##
## LEF for PtnCells ;
## created by Innovus v15.23-s045_1 on Fri Mar  6 05:47:07 2026
##

VERSION 5.8 ;

BUSBITCHARS "[]" ;
DIVIDERCHAR "/" ;

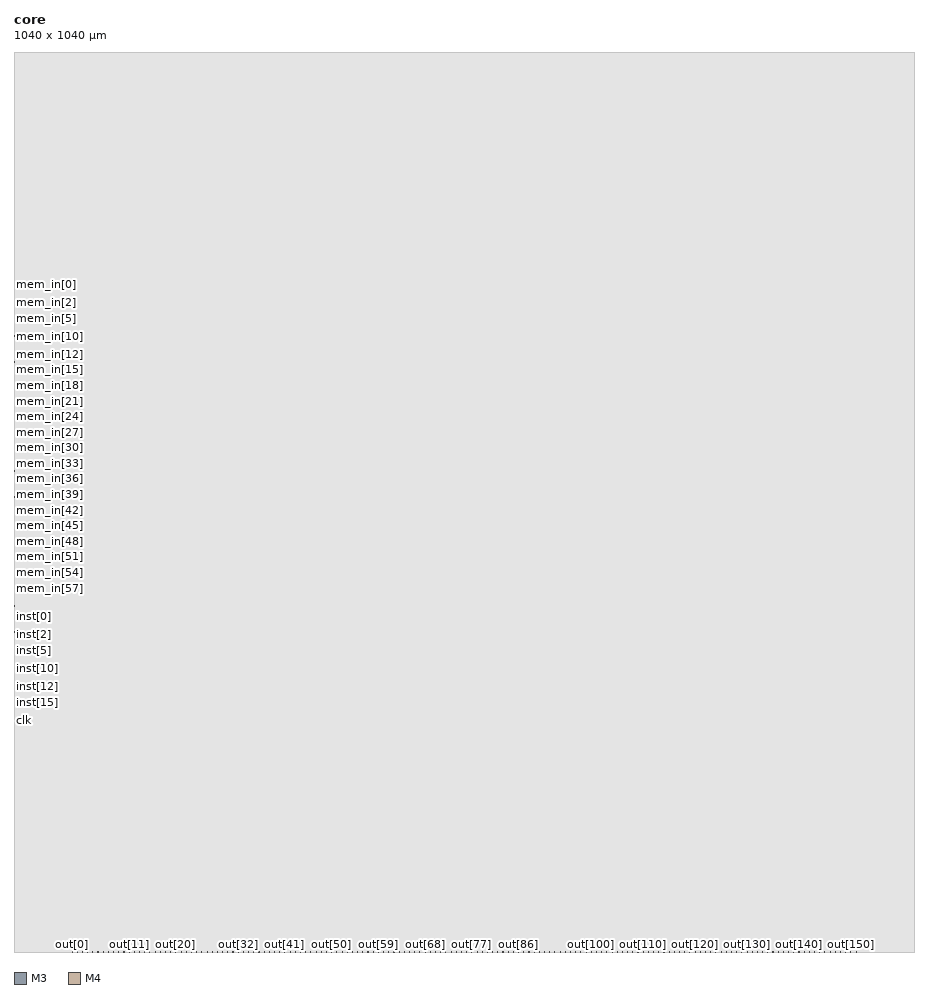
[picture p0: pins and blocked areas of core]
MACRO core
  CLASS BLOCK ;
  SIZE 1040.0000 BY 1040.0000 ;
  FOREIGN core 0.0000 0.0000 ;
  ORIGIN 0 0 ;
  SYMMETRY X Y R90 ;
  PIN clk
    DIRECTION INPUT ;
    USE SIGNAL ;
    PORT
      LAYER M3 ;
        RECT 0.0000 267.7500 0.5200 267.8500 ;
    END
  END clk
  PIN mem_in[63]
    DIRECTION INPUT ;
    USE SIGNAL ;
    PORT
      LAYER M3 ;
        RECT 0.0000 393.7500 0.5200 393.8500 ;
    END
  END mem_in[63]
  PIN mem_in[62]
    DIRECTION INPUT ;
    USE SIGNAL ;
    PORT
      LAYER M3 ;
        RECT 0.0000 399.7500 0.5200 399.8500 ;
    END
  END mem_in[62]
  PIN mem_in[61]
    DIRECTION INPUT ;
    USE SIGNAL ;
    PORT
      LAYER M3 ;
        RECT 0.0000 405.7500 0.5200 405.8500 ;
    END
  END mem_in[61]
  PIN mem_in[60]
    DIRECTION INPUT ;
    USE SIGNAL ;
    PORT
      LAYER M3 ;
        RECT 0.0000 411.7500 0.5200 411.8500 ;
    END
  END mem_in[60]
  PIN mem_in[59]
    DIRECTION INPUT ;
    USE SIGNAL ;
    PORT
      LAYER M3 ;
        RECT 0.0000 417.7500 0.5200 417.8500 ;
    END
  END mem_in[59]
  PIN mem_in[58]
    DIRECTION INPUT ;
    USE SIGNAL ;
    PORT
      LAYER M3 ;
        RECT 0.0000 423.7500 0.5200 423.8500 ;
    END
  END mem_in[58]
  PIN mem_in[57]
    DIRECTION INPUT ;
    USE SIGNAL ;
    PORT
      LAYER M3 ;
        RECT 0.0000 429.7500 0.5200 429.8500 ;
    END
  END mem_in[57]
  PIN mem_in[56]
    DIRECTION INPUT ;
    USE SIGNAL ;
    PORT
      LAYER M3 ;
        RECT 0.0000 435.7500 0.5200 435.8500 ;
    END
  END mem_in[56]
  PIN mem_in[55]
    DIRECTION INPUT ;
    USE SIGNAL ;
    PORT
      LAYER M3 ;
        RECT 0.0000 441.7500 0.5200 441.8500 ;
    END
  END mem_in[55]
  PIN mem_in[54]
    DIRECTION INPUT ;
    USE SIGNAL ;
    PORT
      LAYER M3 ;
        RECT 0.0000 447.7500 0.5200 447.8500 ;
    END
  END mem_in[54]
  PIN mem_in[53]
    DIRECTION INPUT ;
    USE SIGNAL ;
    PORT
      LAYER M3 ;
        RECT 0.0000 453.7500 0.5200 453.8500 ;
    END
  END mem_in[53]
  PIN mem_in[52]
    DIRECTION INPUT ;
    USE SIGNAL ;
    PORT
      LAYER M3 ;
        RECT 0.0000 459.7500 0.5200 459.8500 ;
    END
  END mem_in[52]
  PIN mem_in[51]
    DIRECTION INPUT ;
    USE SIGNAL ;
    PORT
      LAYER M3 ;
        RECT 0.0000 465.7500 0.5200 465.8500 ;
    END
  END mem_in[51]
  PIN mem_in[50]
    DIRECTION INPUT ;
    USE SIGNAL ;
    PORT
      LAYER M3 ;
        RECT 0.0000 471.7500 0.5200 471.8500 ;
    END
  END mem_in[50]
  PIN mem_in[49]
    DIRECTION INPUT ;
    USE SIGNAL ;
    PORT
      LAYER M3 ;
        RECT 0.0000 477.7500 0.5200 477.8500 ;
    END
  END mem_in[49]
  PIN mem_in[48]
    DIRECTION INPUT ;
    USE SIGNAL ;
    PORT
      LAYER M3 ;
        RECT 0.0000 483.7500 0.5200 483.8500 ;
    END
  END mem_in[48]
  PIN mem_in[47]
    DIRECTION INPUT ;
    USE SIGNAL ;
    PORT
      LAYER M3 ;
        RECT 0.0000 489.7500 0.5200 489.8500 ;
    END
  END mem_in[47]
  PIN mem_in[46]
    DIRECTION INPUT ;
    USE SIGNAL ;
    PORT
      LAYER M3 ;
        RECT 0.0000 495.7500 0.5200 495.8500 ;
    END
  END mem_in[46]
  PIN mem_in[45]
    DIRECTION INPUT ;
    USE SIGNAL ;
    PORT
      LAYER M3 ;
        RECT 0.0000 501.7500 0.5200 501.8500 ;
    END
  END mem_in[45]
  PIN mem_in[44]
    DIRECTION INPUT ;
    USE SIGNAL ;
    PORT
      LAYER M3 ;
        RECT 0.0000 507.7500 0.5200 507.8500 ;
    END
  END mem_in[44]
  PIN mem_in[43]
    DIRECTION INPUT ;
    USE SIGNAL ;
    PORT
      LAYER M3 ;
        RECT 0.0000 513.7500 0.5200 513.8500 ;
    END
  END mem_in[43]
  PIN mem_in[42]
    DIRECTION INPUT ;
    USE SIGNAL ;
    PORT
      LAYER M3 ;
        RECT 0.0000 519.7500 0.5200 519.8500 ;
    END
  END mem_in[42]
  PIN mem_in[41]
    DIRECTION INPUT ;
    USE SIGNAL ;
    PORT
      LAYER M3 ;
        RECT 0.0000 525.7500 0.5200 525.8500 ;
    END
  END mem_in[41]
  PIN mem_in[40]
    DIRECTION INPUT ;
    USE SIGNAL ;
    PORT
      LAYER M3 ;
        RECT 0.0000 531.7500 0.5200 531.8500 ;
    END
  END mem_in[40]
  PIN mem_in[39]
    DIRECTION INPUT ;
    USE SIGNAL ;
    PORT
      LAYER M3 ;
        RECT 0.0000 537.7500 0.5200 537.8500 ;
    END
  END mem_in[39]
  PIN mem_in[38]
    DIRECTION INPUT ;
    USE SIGNAL ;
    PORT
      LAYER M3 ;
        RECT 0.0000 543.7500 0.5200 543.8500 ;
    END
  END mem_in[38]
  PIN mem_in[37]
    DIRECTION INPUT ;
    USE SIGNAL ;
    PORT
      LAYER M3 ;
        RECT 0.0000 549.7500 0.5200 549.8500 ;
    END
  END mem_in[37]
  PIN mem_in[36]
    DIRECTION INPUT ;
    USE SIGNAL ;
    PORT
      LAYER M3 ;
        RECT 0.0000 555.7500 0.5200 555.8500 ;
    END
  END mem_in[36]
  PIN mem_in[35]
    DIRECTION INPUT ;
    USE SIGNAL ;
    PORT
      LAYER M3 ;
        RECT 0.0000 561.7500 0.5200 561.8500 ;
    END
  END mem_in[35]
  PIN mem_in[34]
    DIRECTION INPUT ;
    USE SIGNAL ;
    PORT
      LAYER M3 ;
        RECT 0.0000 567.7500 0.5200 567.8500 ;
    END
  END mem_in[34]
  PIN mem_in[33]
    DIRECTION INPUT ;
    USE SIGNAL ;
    PORT
      LAYER M3 ;
        RECT 0.0000 573.7500 0.5200 573.8500 ;
    END
  END mem_in[33]
  PIN mem_in[32]
    DIRECTION INPUT ;
    USE SIGNAL ;
    PORT
      LAYER M3 ;
        RECT 0.0000 579.7500 0.5200 579.8500 ;
    END
  END mem_in[32]
  PIN mem_in[31]
    DIRECTION INPUT ;
    USE SIGNAL ;
    PORT
      LAYER M3 ;
        RECT 0.0000 585.7500 0.5200 585.8500 ;
    END
  END mem_in[31]
  PIN mem_in[30]
    DIRECTION INPUT ;
    USE SIGNAL ;
    PORT
      LAYER M3 ;
        RECT 0.0000 591.7500 0.5200 591.8500 ;
    END
  END mem_in[30]
  PIN mem_in[29]
    DIRECTION INPUT ;
    USE SIGNAL ;
    PORT
      LAYER M3 ;
        RECT 0.0000 597.7500 0.5200 597.8500 ;
    END
  END mem_in[29]
  PIN mem_in[28]
    DIRECTION INPUT ;
    USE SIGNAL ;
    PORT
      LAYER M3 ;
        RECT 0.0000 603.7500 0.5200 603.8500 ;
    END
  END mem_in[28]
  PIN mem_in[27]
    DIRECTION INPUT ;
    USE SIGNAL ;
    PORT
      LAYER M3 ;
        RECT 0.0000 609.7500 0.5200 609.8500 ;
    END
  END mem_in[27]
  PIN mem_in[26]
    DIRECTION INPUT ;
    USE SIGNAL ;
    PORT
      LAYER M3 ;
        RECT 0.0000 615.7500 0.5200 615.8500 ;
    END
  END mem_in[26]
  PIN mem_in[25]
    DIRECTION INPUT ;
    USE SIGNAL ;
    PORT
      LAYER M3 ;
        RECT 0.0000 621.7500 0.5200 621.8500 ;
    END
  END mem_in[25]
  PIN mem_in[24]
    DIRECTION INPUT ;
    USE SIGNAL ;
    PORT
      LAYER M3 ;
        RECT 0.0000 627.7500 0.5200 627.8500 ;
    END
  END mem_in[24]
  PIN mem_in[23]
    DIRECTION INPUT ;
    USE SIGNAL ;
    PORT
      LAYER M3 ;
        RECT 0.0000 633.7500 0.5200 633.8500 ;
    END
  END mem_in[23]
  PIN mem_in[22]
    DIRECTION INPUT ;
    USE SIGNAL ;
    PORT
      LAYER M3 ;
        RECT 0.0000 639.7500 0.5200 639.8500 ;
    END
  END mem_in[22]
  PIN mem_in[21]
    DIRECTION INPUT ;
    USE SIGNAL ;
    PORT
      LAYER M3 ;
        RECT 0.0000 645.7500 0.5200 645.8500 ;
    END
  END mem_in[21]
  PIN mem_in[20]
    DIRECTION INPUT ;
    USE SIGNAL ;
    PORT
      LAYER M3 ;
        RECT 0.0000 651.7500 0.5200 651.8500 ;
    END
  END mem_in[20]
  PIN mem_in[19]
    DIRECTION INPUT ;
    USE SIGNAL ;
    PORT
      LAYER M3 ;
        RECT 0.0000 657.7500 0.5200 657.8500 ;
    END
  END mem_in[19]
  PIN mem_in[18]
    DIRECTION INPUT ;
    USE SIGNAL ;
    PORT
      LAYER M3 ;
        RECT 0.0000 663.7500 0.5200 663.8500 ;
    END
  END mem_in[18]
  PIN mem_in[17]
    DIRECTION INPUT ;
    USE SIGNAL ;
    PORT
      LAYER M3 ;
        RECT 0.0000 669.7500 0.5200 669.8500 ;
    END
  END mem_in[17]
  PIN mem_in[16]
    DIRECTION INPUT ;
    USE SIGNAL ;
    PORT
      LAYER M3 ;
        RECT 0.0000 675.7500 0.5200 675.8500 ;
    END
  END mem_in[16]
  PIN mem_in[15]
    DIRECTION INPUT ;
    USE SIGNAL ;
    PORT
      LAYER M3 ;
        RECT 0.0000 681.7500 0.5200 681.8500 ;
    END
  END mem_in[15]
  PIN mem_in[14]
    DIRECTION INPUT ;
    USE SIGNAL ;
    PORT
      LAYER M3 ;
        RECT 0.0000 687.7500 0.5200 687.8500 ;
    END
  END mem_in[14]
  PIN mem_in[13]
    DIRECTION INPUT ;
    USE SIGNAL ;
    PORT
      LAYER M3 ;
        RECT 0.0000 693.7500 0.5200 693.8500 ;
    END
  END mem_in[13]
  PIN mem_in[12]
    DIRECTION INPUT ;
    USE SIGNAL ;
    PORT
      LAYER M3 ;
        RECT 0.0000 699.7500 0.5200 699.8500 ;
    END
  END mem_in[12]
  PIN mem_in[11]
    DIRECTION INPUT ;
    USE SIGNAL ;
    PORT
      LAYER M3 ;
        RECT 0.0000 705.7500 0.5200 705.8500 ;
    END
  END mem_in[11]
  PIN mem_in[10]
    DIRECTION INPUT ;
    USE SIGNAL ;
    PORT
      LAYER M3 ;
        RECT 0.0000 711.7500 0.5200 711.8500 ;
    END
  END mem_in[10]
  PIN mem_in[9]
    DIRECTION INPUT ;
    USE SIGNAL ;
    PORT
      LAYER M3 ;
        RECT 0.0000 717.7500 0.5200 717.8500 ;
    END
  END mem_in[9]
  PIN mem_in[8]
    DIRECTION INPUT ;
    USE SIGNAL ;
    PORT
      LAYER M3 ;
        RECT 0.0000 723.7500 0.5200 723.8500 ;
    END
  END mem_in[8]
  PIN mem_in[7]
    DIRECTION INPUT ;
    USE SIGNAL ;
    PORT
      LAYER M3 ;
        RECT 0.0000 729.7500 0.5200 729.8500 ;
    END
  END mem_in[7]
  PIN mem_in[6]
    DIRECTION INPUT ;
    USE SIGNAL ;
    PORT
      LAYER M3 ;
        RECT 0.0000 735.7500 0.5200 735.8500 ;
    END
  END mem_in[6]
  PIN mem_in[5]
    DIRECTION INPUT ;
    USE SIGNAL ;
    PORT
      LAYER M3 ;
        RECT 0.0000 741.7500 0.5200 741.8500 ;
    END
  END mem_in[5]
  PIN mem_in[4]
    DIRECTION INPUT ;
    USE SIGNAL ;
    PORT
      LAYER M3 ;
        RECT 0.0000 747.7500 0.5200 747.8500 ;
    END
  END mem_in[4]
  PIN mem_in[3]
    DIRECTION INPUT ;
    USE SIGNAL ;
    PORT
      LAYER M3 ;
        RECT 0.0000 753.7500 0.5200 753.8500 ;
    END
  END mem_in[3]
  PIN mem_in[2]
    DIRECTION INPUT ;
    USE SIGNAL ;
    PORT
      LAYER M3 ;
        RECT 0.0000 759.7500 0.5200 759.8500 ;
    END
  END mem_in[2]
  PIN mem_in[1]
    DIRECTION INPUT ;
    USE SIGNAL ;
    PORT
      LAYER M3 ;
        RECT 0.0000 765.7500 0.5200 765.8500 ;
    END
  END mem_in[1]
  PIN mem_in[0]
    DIRECTION INPUT ;
    USE SIGNAL ;
    PORT
      LAYER M3 ;
        RECT 0.0000 771.7500 0.5200 771.8500 ;
    END
  END mem_in[0]
  PIN inst[18]
    DIRECTION INPUT ;
    USE SIGNAL ;
    PORT
      LAYER M3 ;
        RECT 0.0000 279.7500 0.5200 279.8500 ;
    END
  END inst[18]
  PIN inst[17]
    DIRECTION INPUT ;
    USE SIGNAL ;
    PORT
      LAYER M3 ;
        RECT 0.0000 285.7500 0.5200 285.8500 ;
    END
  END inst[17]
  PIN inst[16]
    DIRECTION INPUT ;
    USE SIGNAL ;
    PORT
      LAYER M3 ;
        RECT 0.0000 291.7500 0.5200 291.8500 ;
    END
  END inst[16]
  PIN inst[15]
    DIRECTION INPUT ;
    USE SIGNAL ;
    PORT
      LAYER M3 ;
        RECT 0.0000 297.7500 0.5200 297.8500 ;
    END
  END inst[15]
  PIN inst[14]
    DIRECTION INPUT ;
    USE SIGNAL ;
    PORT
      LAYER M3 ;
        RECT 0.0000 303.7500 0.5200 303.8500 ;
    END
  END inst[14]
  PIN inst[13]
    DIRECTION INPUT ;
    USE SIGNAL ;
    PORT
      LAYER M3 ;
        RECT 0.0000 309.7500 0.5200 309.8500 ;
    END
  END inst[13]
  PIN inst[12]
    DIRECTION INPUT ;
    USE SIGNAL ;
    PORT
      LAYER M3 ;
        RECT 0.0000 315.7500 0.5200 315.8500 ;
    END
  END inst[12]
  PIN inst[11]
    DIRECTION INPUT ;
    USE SIGNAL ;
    PORT
      LAYER M3 ;
        RECT 0.0000 321.7500 0.5200 321.8500 ;
    END
  END inst[11]
  PIN inst[10]
    DIRECTION INPUT ;
    USE SIGNAL ;
    PORT
      LAYER M3 ;
        RECT 0.0000 327.7500 0.5200 327.8500 ;
    END
  END inst[10]
  PIN inst[9]
    DIRECTION INPUT ;
    USE SIGNAL ;
    PORT
      LAYER M3 ;
        RECT 0.0000 333.7500 0.5200 333.8500 ;
    END
  END inst[9]
  PIN inst[8]
    DIRECTION INPUT ;
    USE SIGNAL ;
    PORT
      LAYER M3 ;
        RECT 0.0000 339.7500 0.5200 339.8500 ;
    END
  END inst[8]
  PIN inst[7]
    DIRECTION INPUT ;
    USE SIGNAL ;
    PORT
      LAYER M3 ;
        RECT 0.0000 345.7500 0.5200 345.8500 ;
    END
  END inst[7]
  PIN inst[6]
    DIRECTION INPUT ;
    USE SIGNAL ;
    PORT
      LAYER M3 ;
        RECT 0.0000 351.7500 0.5200 351.8500 ;
    END
  END inst[6]
  PIN inst[5]
    DIRECTION INPUT ;
    USE SIGNAL ;
    PORT
      LAYER M3 ;
        RECT 0.0000 357.7500 0.5200 357.8500 ;
    END
  END inst[5]
  PIN inst[4]
    DIRECTION INPUT ;
    USE SIGNAL ;
    PORT
      LAYER M3 ;
        RECT 0.0000 363.7500 0.5200 363.8500 ;
    END
  END inst[4]
  PIN inst[3]
    DIRECTION INPUT ;
    USE SIGNAL ;
    PORT
      LAYER M3 ;
        RECT 0.0000 369.7500 0.5200 369.8500 ;
    END
  END inst[3]
  PIN inst[2]
    DIRECTION INPUT ;
    USE SIGNAL ;
    PORT
      LAYER M3 ;
        RECT 0.0000 375.7500 0.5200 375.8500 ;
    END
  END inst[2]
  PIN inst[1]
    DIRECTION INPUT ;
    USE SIGNAL ;
    PORT
      LAYER M3 ;
        RECT 0.0000 381.7500 0.5200 381.8500 ;
    END
  END inst[1]
  PIN inst[0]
    DIRECTION INPUT ;
    USE SIGNAL ;
    PORT
      LAYER M3 ;
        RECT 0.0000 387.7500 0.5200 387.8500 ;
    END
  END inst[0]
  PIN reset
    DIRECTION INPUT ;
    USE SIGNAL ;
    PORT
      LAYER M3 ;
        RECT 0.0000 273.7500 0.5200 273.8500 ;
    END
  END reset
  PIN out[151]
    DIRECTION OUTPUT ;
    USE SIGNAL ;
    PORT
      LAYER M4 ;
        RECT 973.0500 0.0000 973.1500 0.5200 ;
    END
  END out[151]
  PIN out[150]
    DIRECTION OUTPUT ;
    USE SIGNAL ;
    PORT
      LAYER M4 ;
        RECT 967.0500 0.0000 967.1500 0.5200 ;
    END
  END out[150]
  PIN out[149]
    DIRECTION OUTPUT ;
    USE SIGNAL ;
    PORT
      LAYER M4 ;
        RECT 961.0500 0.0000 961.1500 0.5200 ;
    END
  END out[149]
  PIN out[148]
    DIRECTION OUTPUT ;
    USE SIGNAL ;
    PORT
      LAYER M4 ;
        RECT 955.0500 0.0000 955.1500 0.5200 ;
    END
  END out[148]
  PIN out[147]
    DIRECTION OUTPUT ;
    USE SIGNAL ;
    PORT
      LAYER M4 ;
        RECT 949.0500 0.0000 949.1500 0.5200 ;
    END
  END out[147]
  PIN out[146]
    DIRECTION OUTPUT ;
    USE SIGNAL ;
    PORT
      LAYER M4 ;
        RECT 943.0500 0.0000 943.1500 0.5200 ;
    END
  END out[146]
  PIN out[145]
    DIRECTION OUTPUT ;
    USE SIGNAL ;
    PORT
      LAYER M4 ;
        RECT 937.0500 0.0000 937.1500 0.5200 ;
    END
  END out[145]
  PIN out[144]
    DIRECTION OUTPUT ;
    USE SIGNAL ;
    PORT
      LAYER M4 ;
        RECT 931.0500 0.0000 931.1500 0.5200 ;
    END
  END out[144]
  PIN out[143]
    DIRECTION OUTPUT ;
    USE SIGNAL ;
    PORT
      LAYER M4 ;
        RECT 925.0500 0.0000 925.1500 0.5200 ;
    END
  END out[143]
  PIN out[142]
    DIRECTION OUTPUT ;
    USE SIGNAL ;
    PORT
      LAYER M4 ;
        RECT 919.0500 0.0000 919.1500 0.5200 ;
    END
  END out[142]
  PIN out[141]
    DIRECTION OUTPUT ;
    USE SIGNAL ;
    PORT
      LAYER M4 ;
        RECT 913.0500 0.0000 913.1500 0.5200 ;
    END
  END out[141]
  PIN out[140]
    DIRECTION OUTPUT ;
    USE SIGNAL ;
    PORT
      LAYER M4 ;
        RECT 907.0500 0.0000 907.1500 0.5200 ;
    END
  END out[140]
  PIN out[139]
    DIRECTION OUTPUT ;
    USE SIGNAL ;
    PORT
      LAYER M4 ;
        RECT 901.0500 0.0000 901.1500 0.5200 ;
    END
  END out[139]
  PIN out[138]
    DIRECTION OUTPUT ;
    USE SIGNAL ;
    PORT
      LAYER M4 ;
        RECT 895.0500 0.0000 895.1500 0.5200 ;
    END
  END out[138]
  PIN out[137]
    DIRECTION OUTPUT ;
    USE SIGNAL ;
    PORT
      LAYER M4 ;
        RECT 889.0500 0.0000 889.1500 0.5200 ;
    END
  END out[137]
  PIN out[136]
    DIRECTION OUTPUT ;
    USE SIGNAL ;
    PORT
      LAYER M4 ;
        RECT 883.0500 0.0000 883.1500 0.5200 ;
    END
  END out[136]
  PIN out[135]
    DIRECTION OUTPUT ;
    USE SIGNAL ;
    PORT
      LAYER M4 ;
        RECT 877.0500 0.0000 877.1500 0.5200 ;
    END
  END out[135]
  PIN out[134]
    DIRECTION OUTPUT ;
    USE SIGNAL ;
    PORT
      LAYER M4 ;
        RECT 871.0500 0.0000 871.1500 0.5200 ;
    END
  END out[134]
  PIN out[133]
    DIRECTION OUTPUT ;
    USE SIGNAL ;
    PORT
      LAYER M4 ;
        RECT 865.0500 0.0000 865.1500 0.5200 ;
    END
  END out[133]
  PIN out[132]
    DIRECTION OUTPUT ;
    USE SIGNAL ;
    PORT
      LAYER M4 ;
        RECT 859.0500 0.0000 859.1500 0.5200 ;
    END
  END out[132]
  PIN out[131]
    DIRECTION OUTPUT ;
    USE SIGNAL ;
    PORT
      LAYER M4 ;
        RECT 853.0500 0.0000 853.1500 0.5200 ;
    END
  END out[131]
  PIN out[130]
    DIRECTION OUTPUT ;
    USE SIGNAL ;
    PORT
      LAYER M4 ;
        RECT 847.0500 0.0000 847.1500 0.5200 ;
    END
  END out[130]
  PIN out[129]
    DIRECTION OUTPUT ;
    USE SIGNAL ;
    PORT
      LAYER M4 ;
        RECT 841.0500 0.0000 841.1500 0.5200 ;
    END
  END out[129]
  PIN out[128]
    DIRECTION OUTPUT ;
    USE SIGNAL ;
    PORT
      LAYER M4 ;
        RECT 835.0500 0.0000 835.1500 0.5200 ;
    END
  END out[128]
  PIN out[127]
    DIRECTION OUTPUT ;
    USE SIGNAL ;
    PORT
      LAYER M4 ;
        RECT 829.0500 0.0000 829.1500 0.5200 ;
    END
  END out[127]
  PIN out[126]
    DIRECTION OUTPUT ;
    USE SIGNAL ;
    PORT
      LAYER M4 ;
        RECT 823.0500 0.0000 823.1500 0.5200 ;
    END
  END out[126]
  PIN out[125]
    DIRECTION OUTPUT ;
    USE SIGNAL ;
    PORT
      LAYER M4 ;
        RECT 817.0500 0.0000 817.1500 0.5200 ;
    END
  END out[125]
  PIN out[124]
    DIRECTION OUTPUT ;
    USE SIGNAL ;
    PORT
      LAYER M4 ;
        RECT 811.0500 0.0000 811.1500 0.5200 ;
    END
  END out[124]
  PIN out[123]
    DIRECTION OUTPUT ;
    USE SIGNAL ;
    PORT
      LAYER M4 ;
        RECT 805.0500 0.0000 805.1500 0.5200 ;
    END
  END out[123]
  PIN out[122]
    DIRECTION OUTPUT ;
    USE SIGNAL ;
    PORT
      LAYER M4 ;
        RECT 799.0500 0.0000 799.1500 0.5200 ;
    END
  END out[122]
  PIN out[121]
    DIRECTION OUTPUT ;
    USE SIGNAL ;
    PORT
      LAYER M4 ;
        RECT 793.0500 0.0000 793.1500 0.5200 ;
    END
  END out[121]
  PIN out[120]
    DIRECTION OUTPUT ;
    USE SIGNAL ;
    PORT
      LAYER M4 ;
        RECT 787.0500 0.0000 787.1500 0.5200 ;
    END
  END out[120]
  PIN out[119]
    DIRECTION OUTPUT ;
    USE SIGNAL ;
    PORT
      LAYER M4 ;
        RECT 781.0500 0.0000 781.1500 0.5200 ;
    END
  END out[119]
  PIN out[118]
    DIRECTION OUTPUT ;
    USE SIGNAL ;
    PORT
      LAYER M4 ;
        RECT 775.0500 0.0000 775.1500 0.5200 ;
    END
  END out[118]
  PIN out[117]
    DIRECTION OUTPUT ;
    USE SIGNAL ;
    PORT
      LAYER M4 ;
        RECT 769.0500 0.0000 769.1500 0.5200 ;
    END
  END out[117]
  PIN out[116]
    DIRECTION OUTPUT ;
    USE SIGNAL ;
    PORT
      LAYER M4 ;
        RECT 763.0500 0.0000 763.1500 0.5200 ;
    END
  END out[116]
  PIN out[115]
    DIRECTION OUTPUT ;
    USE SIGNAL ;
    PORT
      LAYER M4 ;
        RECT 757.0500 0.0000 757.1500 0.5200 ;
    END
  END out[115]
  PIN out[114]
    DIRECTION OUTPUT ;
    USE SIGNAL ;
    PORT
      LAYER M4 ;
        RECT 751.0500 0.0000 751.1500 0.5200 ;
    END
  END out[114]
  PIN out[113]
    DIRECTION OUTPUT ;
    USE SIGNAL ;
    PORT
      LAYER M4 ;
        RECT 745.0500 0.0000 745.1500 0.5200 ;
    END
  END out[113]
  PIN out[112]
    DIRECTION OUTPUT ;
    USE SIGNAL ;
    PORT
      LAYER M4 ;
        RECT 739.0500 0.0000 739.1500 0.5200 ;
    END
  END out[112]
  PIN out[111]
    DIRECTION OUTPUT ;
    USE SIGNAL ;
    PORT
      LAYER M4 ;
        RECT 733.0500 0.0000 733.1500 0.5200 ;
    END
  END out[111]
  PIN out[110]
    DIRECTION OUTPUT ;
    USE SIGNAL ;
    PORT
      LAYER M4 ;
        RECT 727.0500 0.0000 727.1500 0.5200 ;
    END
  END out[110]
  PIN out[109]
    DIRECTION OUTPUT ;
    USE SIGNAL ;
    PORT
      LAYER M4 ;
        RECT 721.0500 0.0000 721.1500 0.5200 ;
    END
  END out[109]
  PIN out[108]
    DIRECTION OUTPUT ;
    USE SIGNAL ;
    PORT
      LAYER M4 ;
        RECT 715.0500 0.0000 715.1500 0.5200 ;
    END
  END out[108]
  PIN out[107]
    DIRECTION OUTPUT ;
    USE SIGNAL ;
    PORT
      LAYER M4 ;
        RECT 709.0500 0.0000 709.1500 0.5200 ;
    END
  END out[107]
  PIN out[106]
    DIRECTION OUTPUT ;
    USE SIGNAL ;
    PORT
      LAYER M4 ;
        RECT 703.0500 0.0000 703.1500 0.5200 ;
    END
  END out[106]
  PIN out[105]
    DIRECTION OUTPUT ;
    USE SIGNAL ;
    PORT
      LAYER M4 ;
        RECT 697.0500 0.0000 697.1500 0.5200 ;
    END
  END out[105]
  PIN out[104]
    DIRECTION OUTPUT ;
    USE SIGNAL ;
    PORT
      LAYER M4 ;
        RECT 691.0500 0.0000 691.1500 0.5200 ;
    END
  END out[104]
  PIN out[103]
    DIRECTION OUTPUT ;
    USE SIGNAL ;
    PORT
      LAYER M4 ;
        RECT 685.0500 0.0000 685.1500 0.5200 ;
    END
  END out[103]
  PIN out[102]
    DIRECTION OUTPUT ;
    USE SIGNAL ;
    PORT
      LAYER M4 ;
        RECT 679.0500 0.0000 679.1500 0.5200 ;
    END
  END out[102]
  PIN out[101]
    DIRECTION OUTPUT ;
    USE SIGNAL ;
    PORT
      LAYER M4 ;
        RECT 673.0500 0.0000 673.1500 0.5200 ;
    END
  END out[101]
  PIN out[100]
    DIRECTION OUTPUT ;
    USE SIGNAL ;
    PORT
      LAYER M4 ;
        RECT 667.0500 0.0000 667.1500 0.5200 ;
    END
  END out[100]
  PIN out[99]
    DIRECTION OUTPUT ;
    USE SIGNAL ;
    PORT
      LAYER M4 ;
        RECT 661.0500 0.0000 661.1500 0.5200 ;
    END
  END out[99]
  PIN out[98]
    DIRECTION OUTPUT ;
    USE SIGNAL ;
    PORT
      LAYER M4 ;
        RECT 655.0500 0.0000 655.1500 0.5200 ;
    END
  END out[98]
  PIN out[97]
    DIRECTION OUTPUT ;
    USE SIGNAL ;
    PORT
      LAYER M4 ;
        RECT 649.0500 0.0000 649.1500 0.5200 ;
    END
  END out[97]
  PIN out[96]
    DIRECTION OUTPUT ;
    USE SIGNAL ;
    PORT
      LAYER M4 ;
        RECT 643.0500 0.0000 643.1500 0.5200 ;
    END
  END out[96]
  PIN out[95]
    DIRECTION OUTPUT ;
    USE SIGNAL ;
    PORT
      LAYER M4 ;
        RECT 637.0500 0.0000 637.1500 0.5200 ;
    END
  END out[95]
  PIN out[94]
    DIRECTION OUTPUT ;
    USE SIGNAL ;
    PORT
      LAYER M4 ;
        RECT 631.0500 0.0000 631.1500 0.5200 ;
    END
  END out[94]
  PIN out[93]
    DIRECTION OUTPUT ;
    USE SIGNAL ;
    PORT
      LAYER M4 ;
        RECT 625.0500 0.0000 625.1500 0.5200 ;
    END
  END out[93]
  PIN out[92]
    DIRECTION OUTPUT ;
    USE SIGNAL ;
    PORT
      LAYER M4 ;
        RECT 619.0500 0.0000 619.1500 0.5200 ;
    END
  END out[92]
  PIN out[91]
    DIRECTION OUTPUT ;
    USE SIGNAL ;
    PORT
      LAYER M4 ;
        RECT 613.0500 0.0000 613.1500 0.5200 ;
    END
  END out[91]
  PIN out[90]
    DIRECTION OUTPUT ;
    USE SIGNAL ;
    PORT
      LAYER M4 ;
        RECT 607.0500 0.0000 607.1500 0.5200 ;
    END
  END out[90]
  PIN out[89]
    DIRECTION OUTPUT ;
    USE SIGNAL ;
    PORT
      LAYER M4 ;
        RECT 601.0500 0.0000 601.1500 0.5200 ;
    END
  END out[89]
  PIN out[88]
    DIRECTION OUTPUT ;
    USE SIGNAL ;
    PORT
      LAYER M4 ;
        RECT 595.0500 0.0000 595.1500 0.5200 ;
    END
  END out[88]
  PIN out[87]
    DIRECTION OUTPUT ;
    USE SIGNAL ;
    PORT
      LAYER M4 ;
        RECT 589.0500 0.0000 589.1500 0.5200 ;
    END
  END out[87]
  PIN out[86]
    DIRECTION OUTPUT ;
    USE SIGNAL ;
    PORT
      LAYER M4 ;
        RECT 583.0500 0.0000 583.1500 0.5200 ;
    END
  END out[86]
  PIN out[85]
    DIRECTION OUTPUT ;
    USE SIGNAL ;
    PORT
      LAYER M4 ;
        RECT 577.0500 0.0000 577.1500 0.5200 ;
    END
  END out[85]
  PIN out[84]
    DIRECTION OUTPUT ;
    USE SIGNAL ;
    PORT
      LAYER M4 ;
        RECT 571.0500 0.0000 571.1500 0.5200 ;
    END
  END out[84]
  PIN out[83]
    DIRECTION OUTPUT ;
    USE SIGNAL ;
    PORT
      LAYER M4 ;
        RECT 565.0500 0.0000 565.1500 0.5200 ;
    END
  END out[83]
  PIN out[82]
    DIRECTION OUTPUT ;
    USE SIGNAL ;
    PORT
      LAYER M4 ;
        RECT 559.0500 0.0000 559.1500 0.5200 ;
    END
  END out[82]
  PIN out[81]
    DIRECTION OUTPUT ;
    USE SIGNAL ;
    PORT
      LAYER M4 ;
        RECT 553.0500 0.0000 553.1500 0.5200 ;
    END
  END out[81]
  PIN out[80]
    DIRECTION OUTPUT ;
    USE SIGNAL ;
    PORT
      LAYER M4 ;
        RECT 547.0500 0.0000 547.1500 0.5200 ;
    END
  END out[80]
  PIN out[79]
    DIRECTION OUTPUT ;
    USE SIGNAL ;
    PORT
      LAYER M4 ;
        RECT 541.0500 0.0000 541.1500 0.5200 ;
    END
  END out[79]
  PIN out[78]
    DIRECTION OUTPUT ;
    USE SIGNAL ;
    PORT
      LAYER M4 ;
        RECT 535.0500 0.0000 535.1500 0.5200 ;
    END
  END out[78]
  PIN out[77]
    DIRECTION OUTPUT ;
    USE SIGNAL ;
    PORT
      LAYER M4 ;
        RECT 529.0500 0.0000 529.1500 0.5200 ;
    END
  END out[77]
  PIN out[76]
    DIRECTION OUTPUT ;
    USE SIGNAL ;
    PORT
      LAYER M4 ;
        RECT 523.0500 0.0000 523.1500 0.5200 ;
    END
  END out[76]
  PIN out[75]
    DIRECTION OUTPUT ;
    USE SIGNAL ;
    PORT
      LAYER M4 ;
        RECT 517.0500 0.0000 517.1500 0.5200 ;
    END
  END out[75]
  PIN out[74]
    DIRECTION OUTPUT ;
    USE SIGNAL ;
    PORT
      LAYER M4 ;
        RECT 511.0500 0.0000 511.1500 0.5200 ;
    END
  END out[74]
  PIN out[73]
    DIRECTION OUTPUT ;
    USE SIGNAL ;
    PORT
      LAYER M4 ;
        RECT 505.0500 0.0000 505.1500 0.5200 ;
    END
  END out[73]
  PIN out[72]
    DIRECTION OUTPUT ;
    USE SIGNAL ;
    PORT
      LAYER M4 ;
        RECT 499.0500 0.0000 499.1500 0.5200 ;
    END
  END out[72]
  PIN out[71]
    DIRECTION OUTPUT ;
    USE SIGNAL ;
    PORT
      LAYER M4 ;
        RECT 493.0500 0.0000 493.1500 0.5200 ;
    END
  END out[71]
  PIN out[70]
    DIRECTION OUTPUT ;
    USE SIGNAL ;
    PORT
      LAYER M4 ;
        RECT 487.0500 0.0000 487.1500 0.5200 ;
    END
  END out[70]
  PIN out[69]
    DIRECTION OUTPUT ;
    USE SIGNAL ;
    PORT
      LAYER M4 ;
        RECT 481.0500 0.0000 481.1500 0.5200 ;
    END
  END out[69]
  PIN out[68]
    DIRECTION OUTPUT ;
    USE SIGNAL ;
    PORT
      LAYER M4 ;
        RECT 475.0500 0.0000 475.1500 0.5200 ;
    END
  END out[68]
  PIN out[67]
    DIRECTION OUTPUT ;
    USE SIGNAL ;
    PORT
      LAYER M4 ;
        RECT 469.0500 0.0000 469.1500 0.5200 ;
    END
  END out[67]
  PIN out[66]
    DIRECTION OUTPUT ;
    USE SIGNAL ;
    PORT
      LAYER M4 ;
        RECT 463.0500 0.0000 463.1500 0.5200 ;
    END
  END out[66]
  PIN out[65]
    DIRECTION OUTPUT ;
    USE SIGNAL ;
    PORT
      LAYER M4 ;
        RECT 457.0500 0.0000 457.1500 0.5200 ;
    END
  END out[65]
  PIN out[64]
    DIRECTION OUTPUT ;
    USE SIGNAL ;
    PORT
      LAYER M4 ;
        RECT 451.0500 0.0000 451.1500 0.5200 ;
    END
  END out[64]
  PIN out[63]
    DIRECTION OUTPUT ;
    USE SIGNAL ;
    PORT
      LAYER M4 ;
        RECT 445.0500 0.0000 445.1500 0.5200 ;
    END
  END out[63]
  PIN out[62]
    DIRECTION OUTPUT ;
    USE SIGNAL ;
    PORT
      LAYER M4 ;
        RECT 439.0500 0.0000 439.1500 0.5200 ;
    END
  END out[62]
  PIN out[61]
    DIRECTION OUTPUT ;
    USE SIGNAL ;
    PORT
      LAYER M4 ;
        RECT 433.0500 0.0000 433.1500 0.5200 ;
    END
  END out[61]
  PIN out[60]
    DIRECTION OUTPUT ;
    USE SIGNAL ;
    PORT
      LAYER M4 ;
        RECT 427.0500 0.0000 427.1500 0.5200 ;
    END
  END out[60]
  PIN out[59]
    DIRECTION OUTPUT ;
    USE SIGNAL ;
    PORT
      LAYER M4 ;
        RECT 421.0500 0.0000 421.1500 0.5200 ;
    END
  END out[59]
  PIN out[58]
    DIRECTION OUTPUT ;
    USE SIGNAL ;
    PORT
      LAYER M4 ;
        RECT 415.0500 0.0000 415.1500 0.5200 ;
    END
  END out[58]
  PIN out[57]
    DIRECTION OUTPUT ;
    USE SIGNAL ;
    PORT
      LAYER M4 ;
        RECT 409.0500 0.0000 409.1500 0.5200 ;
    END
  END out[57]
  PIN out[56]
    DIRECTION OUTPUT ;
    USE SIGNAL ;
    PORT
      LAYER M4 ;
        RECT 403.0500 0.0000 403.1500 0.5200 ;
    END
  END out[56]
  PIN out[55]
    DIRECTION OUTPUT ;
    USE SIGNAL ;
    PORT
      LAYER M4 ;
        RECT 397.0500 0.0000 397.1500 0.5200 ;
    END
  END out[55]
  PIN out[54]
    DIRECTION OUTPUT ;
    USE SIGNAL ;
    PORT
      LAYER M4 ;
        RECT 391.0500 0.0000 391.1500 0.5200 ;
    END
  END out[54]
  PIN out[53]
    DIRECTION OUTPUT ;
    USE SIGNAL ;
    PORT
      LAYER M4 ;
        RECT 385.0500 0.0000 385.1500 0.5200 ;
    END
  END out[53]
  PIN out[52]
    DIRECTION OUTPUT ;
    USE SIGNAL ;
    PORT
      LAYER M4 ;
        RECT 379.0500 0.0000 379.1500 0.5200 ;
    END
  END out[52]
  PIN out[51]
    DIRECTION OUTPUT ;
    USE SIGNAL ;
    PORT
      LAYER M4 ;
        RECT 373.0500 0.0000 373.1500 0.5200 ;
    END
  END out[51]
  PIN out[50]
    DIRECTION OUTPUT ;
    USE SIGNAL ;
    PORT
      LAYER M4 ;
        RECT 367.0500 0.0000 367.1500 0.5200 ;
    END
  END out[50]
  PIN out[49]
    DIRECTION OUTPUT ;
    USE SIGNAL ;
    PORT
      LAYER M4 ;
        RECT 361.0500 0.0000 361.1500 0.5200 ;
    END
  END out[49]
  PIN out[48]
    DIRECTION OUTPUT ;
    USE SIGNAL ;
    PORT
      LAYER M4 ;
        RECT 355.0500 0.0000 355.1500 0.5200 ;
    END
  END out[48]
  PIN out[47]
    DIRECTION OUTPUT ;
    USE SIGNAL ;
    PORT
      LAYER M4 ;
        RECT 349.0500 0.0000 349.1500 0.5200 ;
    END
  END out[47]
  PIN out[46]
    DIRECTION OUTPUT ;
    USE SIGNAL ;
    PORT
      LAYER M4 ;
        RECT 343.0500 0.0000 343.1500 0.5200 ;
    END
  END out[46]
  PIN out[45]
    DIRECTION OUTPUT ;
    USE SIGNAL ;
    PORT
      LAYER M4 ;
        RECT 337.0500 0.0000 337.1500 0.5200 ;
    END
  END out[45]
  PIN out[44]
    DIRECTION OUTPUT ;
    USE SIGNAL ;
    PORT
      LAYER M4 ;
        RECT 331.0500 0.0000 331.1500 0.5200 ;
    END
  END out[44]
  PIN out[43]
    DIRECTION OUTPUT ;
    USE SIGNAL ;
    PORT
      LAYER M4 ;
        RECT 325.0500 0.0000 325.1500 0.5200 ;
    END
  END out[43]
  PIN out[42]
    DIRECTION OUTPUT ;
    USE SIGNAL ;
    PORT
      LAYER M4 ;
        RECT 319.0500 0.0000 319.1500 0.5200 ;
    END
  END out[42]
  PIN out[41]
    DIRECTION OUTPUT ;
    USE SIGNAL ;
    PORT
      LAYER M4 ;
        RECT 313.0500 0.0000 313.1500 0.5200 ;
    END
  END out[41]
  PIN out[40]
    DIRECTION OUTPUT ;
    USE SIGNAL ;
    PORT
      LAYER M4 ;
        RECT 307.0500 0.0000 307.1500 0.5200 ;
    END
  END out[40]
  PIN out[39]
    DIRECTION OUTPUT ;
    USE SIGNAL ;
    PORT
      LAYER M4 ;
        RECT 301.0500 0.0000 301.1500 0.5200 ;
    END
  END out[39]
  PIN out[38]
    DIRECTION OUTPUT ;
    USE SIGNAL ;
    PORT
      LAYER M4 ;
        RECT 295.0500 0.0000 295.1500 0.5200 ;
    END
  END out[38]
  PIN out[37]
    DIRECTION OUTPUT ;
    USE SIGNAL ;
    PORT
      LAYER M4 ;
        RECT 289.0500 0.0000 289.1500 0.5200 ;
    END
  END out[37]
  PIN out[36]
    DIRECTION OUTPUT ;
    USE SIGNAL ;
    PORT
      LAYER M4 ;
        RECT 283.0500 0.0000 283.1500 0.5200 ;
    END
  END out[36]
  PIN out[35]
    DIRECTION OUTPUT ;
    USE SIGNAL ;
    PORT
      LAYER M4 ;
        RECT 277.0500 0.0000 277.1500 0.5200 ;
    END
  END out[35]
  PIN out[34]
    DIRECTION OUTPUT ;
    USE SIGNAL ;
    PORT
      LAYER M4 ;
        RECT 271.0500 0.0000 271.1500 0.5200 ;
    END
  END out[34]
  PIN out[33]
    DIRECTION OUTPUT ;
    USE SIGNAL ;
    PORT
      LAYER M4 ;
        RECT 265.0500 0.0000 265.1500 0.5200 ;
    END
  END out[33]
  PIN out[32]
    DIRECTION OUTPUT ;
    USE SIGNAL ;
    PORT
      LAYER M4 ;
        RECT 259.0500 0.0000 259.1500 0.5200 ;
    END
  END out[32]
  PIN out[31]
    DIRECTION OUTPUT ;
    USE SIGNAL ;
    PORT
      LAYER M4 ;
        RECT 253.0500 0.0000 253.1500 0.5200 ;
    END
  END out[31]
  PIN out[30]
    DIRECTION OUTPUT ;
    USE SIGNAL ;
    PORT
      LAYER M4 ;
        RECT 247.0500 0.0000 247.1500 0.5200 ;
    END
  END out[30]
  PIN out[29]
    DIRECTION OUTPUT ;
    USE SIGNAL ;
    PORT
      LAYER M4 ;
        RECT 241.0500 0.0000 241.1500 0.5200 ;
    END
  END out[29]
  PIN out[28]
    DIRECTION OUTPUT ;
    USE SIGNAL ;
    PORT
      LAYER M4 ;
        RECT 235.0500 0.0000 235.1500 0.5200 ;
    END
  END out[28]
  PIN out[27]
    DIRECTION OUTPUT ;
    USE SIGNAL ;
    PORT
      LAYER M4 ;
        RECT 229.0500 0.0000 229.1500 0.5200 ;
    END
  END out[27]
  PIN out[26]
    DIRECTION OUTPUT ;
    USE SIGNAL ;
    PORT
      LAYER M4 ;
        RECT 223.0500 0.0000 223.1500 0.5200 ;
    END
  END out[26]
  PIN out[25]
    DIRECTION OUTPUT ;
    USE SIGNAL ;
    PORT
      LAYER M4 ;
        RECT 217.0500 0.0000 217.1500 0.5200 ;
    END
  END out[25]
  PIN out[24]
    DIRECTION OUTPUT ;
    USE SIGNAL ;
    PORT
      LAYER M4 ;
        RECT 211.0500 0.0000 211.1500 0.5200 ;
    END
  END out[24]
  PIN out[23]
    DIRECTION OUTPUT ;
    USE SIGNAL ;
    PORT
      LAYER M4 ;
        RECT 205.0500 0.0000 205.1500 0.5200 ;
    END
  END out[23]
  PIN out[22]
    DIRECTION OUTPUT ;
    USE SIGNAL ;
    PORT
      LAYER M4 ;
        RECT 199.0500 0.0000 199.1500 0.5200 ;
    END
  END out[22]
  PIN out[21]
    DIRECTION OUTPUT ;
    USE SIGNAL ;
    PORT
      LAYER M4 ;
        RECT 193.0500 0.0000 193.1500 0.5200 ;
    END
  END out[21]
  PIN out[20]
    DIRECTION OUTPUT ;
    USE SIGNAL ;
    PORT
      LAYER M4 ;
        RECT 187.0500 0.0000 187.1500 0.5200 ;
    END
  END out[20]
  PIN out[19]
    DIRECTION OUTPUT ;
    USE SIGNAL ;
    PORT
      LAYER M4 ;
        RECT 181.0500 0.0000 181.1500 0.5200 ;
    END
  END out[19]
  PIN out[18]
    DIRECTION OUTPUT ;
    USE SIGNAL ;
    PORT
      LAYER M4 ;
        RECT 175.0500 0.0000 175.1500 0.5200 ;
    END
  END out[18]
  PIN out[17]
    DIRECTION OUTPUT ;
    USE SIGNAL ;
    PORT
      LAYER M4 ;
        RECT 169.0500 0.0000 169.1500 0.5200 ;
    END
  END out[17]
  PIN out[16]
    DIRECTION OUTPUT ;
    USE SIGNAL ;
    PORT
      LAYER M4 ;
        RECT 163.0500 0.0000 163.1500 0.5200 ;
    END
  END out[16]
  PIN out[15]
    DIRECTION OUTPUT ;
    USE SIGNAL ;
    PORT
      LAYER M4 ;
        RECT 157.0500 0.0000 157.1500 0.5200 ;
    END
  END out[15]
  PIN out[14]
    DIRECTION OUTPUT ;
    USE SIGNAL ;
    PORT
      LAYER M4 ;
        RECT 151.0500 0.0000 151.1500 0.5200 ;
    END
  END out[14]
  PIN out[13]
    DIRECTION OUTPUT ;
    USE SIGNAL ;
    PORT
      LAYER M4 ;
        RECT 145.0500 0.0000 145.1500 0.5200 ;
    END
  END out[13]
  PIN out[12]
    DIRECTION OUTPUT ;
    USE SIGNAL ;
    PORT
      LAYER M4 ;
        RECT 139.0500 0.0000 139.1500 0.5200 ;
    END
  END out[12]
  PIN out[11]
    DIRECTION OUTPUT ;
    USE SIGNAL ;
    PORT
      LAYER M4 ;
        RECT 133.0500 0.0000 133.1500 0.5200 ;
    END
  END out[11]
  PIN out[10]
    DIRECTION OUTPUT ;
    USE SIGNAL ;
    PORT
      LAYER M4 ;
        RECT 127.0500 0.0000 127.1500 0.5200 ;
    END
  END out[10]
  PIN out[9]
    DIRECTION OUTPUT ;
    USE SIGNAL ;
    PORT
      LAYER M4 ;
        RECT 121.0500 0.0000 121.1500 0.5200 ;
    END
  END out[9]
  PIN out[8]
    DIRECTION OUTPUT ;
    USE SIGNAL ;
    PORT
      LAYER M4 ;
        RECT 115.0500 0.0000 115.1500 0.5200 ;
    END
  END out[8]
  PIN out[7]
    DIRECTION OUTPUT ;
    USE SIGNAL ;
    PORT
      LAYER M4 ;
        RECT 109.0500 0.0000 109.1500 0.5200 ;
    END
  END out[7]
  PIN out[6]
    DIRECTION OUTPUT ;
    USE SIGNAL ;
    PORT
      LAYER M4 ;
        RECT 103.0500 0.0000 103.1500 0.5200 ;
    END
  END out[6]
  PIN out[5]
    DIRECTION OUTPUT ;
    USE SIGNAL ;
    PORT
      LAYER M4 ;
        RECT 97.0500 0.0000 97.1500 0.5200 ;
    END
  END out[5]
  PIN out[4]
    DIRECTION OUTPUT ;
    USE SIGNAL ;
    PORT
      LAYER M4 ;
        RECT 91.0500 0.0000 91.1500 0.5200 ;
    END
  END out[4]
  PIN out[3]
    DIRECTION OUTPUT ;
    USE SIGNAL ;
    PORT
      LAYER M4 ;
        RECT 85.0500 0.0000 85.1500 0.5200 ;
    END
  END out[3]
  PIN out[2]
    DIRECTION OUTPUT ;
    USE SIGNAL ;
    PORT
      LAYER M4 ;
        RECT 79.0500 0.0000 79.1500 0.5200 ;
    END
  END out[2]
  PIN out[1]
    DIRECTION OUTPUT ;
    USE SIGNAL ;
    PORT
      LAYER M4 ;
        RECT 73.0500 0.0000 73.1500 0.5200 ;
    END
  END out[1]
  PIN out[0]
    DIRECTION OUTPUT ;
    USE SIGNAL ;
    PORT
      LAYER M4 ;
        RECT 67.0500 0.0000 67.1500 0.5200 ;
    END
  END out[0]
  OBS
    LAYER M1 ;
      RECT 0.0000 0.0000 1040.0000 1040.0000 ;
    LAYER M2 ;
      RECT 0.0000 0.0000 1040.0000 1040.0000 ;
    LAYER M3 ;
      RECT 0.0000 771.9500 1040.0000 1040.0000 ;
      RECT 0.6200 771.6500 1040.0000 771.9500 ;
      RECT 0.0000 765.9500 1040.0000 771.6500 ;
      RECT 0.6200 765.6500 1040.0000 765.9500 ;
      RECT 0.0000 759.9500 1040.0000 765.6500 ;
      RECT 0.6200 759.6500 1040.0000 759.9500 ;
      RECT 0.0000 753.9500 1040.0000 759.6500 ;
      RECT 0.6200 753.6500 1040.0000 753.9500 ;
      RECT 0.0000 747.9500 1040.0000 753.6500 ;
      RECT 0.6200 747.6500 1040.0000 747.9500 ;
      RECT 0.0000 741.9500 1040.0000 747.6500 ;
      RECT 0.6200 741.6500 1040.0000 741.9500 ;
      RECT 0.0000 735.9500 1040.0000 741.6500 ;
      RECT 0.6200 735.6500 1040.0000 735.9500 ;
      RECT 0.0000 729.9500 1040.0000 735.6500 ;
      RECT 0.6200 729.6500 1040.0000 729.9500 ;
      RECT 0.0000 723.9500 1040.0000 729.6500 ;
      RECT 0.6200 723.6500 1040.0000 723.9500 ;
      RECT 0.0000 717.9500 1040.0000 723.6500 ;
      RECT 0.6200 717.6500 1040.0000 717.9500 ;
      RECT 0.0000 711.9500 1040.0000 717.6500 ;
      RECT 0.6200 711.6500 1040.0000 711.9500 ;
      RECT 0.0000 705.9500 1040.0000 711.6500 ;
      RECT 0.6200 705.6500 1040.0000 705.9500 ;
      RECT 0.0000 699.9500 1040.0000 705.6500 ;
      RECT 0.6200 699.6500 1040.0000 699.9500 ;
      RECT 0.0000 693.9500 1040.0000 699.6500 ;
      RECT 0.6200 693.6500 1040.0000 693.9500 ;
      RECT 0.0000 687.9500 1040.0000 693.6500 ;
      RECT 0.6200 687.6500 1040.0000 687.9500 ;
      RECT 0.0000 681.9500 1040.0000 687.6500 ;
      RECT 0.6200 681.6500 1040.0000 681.9500 ;
      RECT 0.0000 675.9500 1040.0000 681.6500 ;
      RECT 0.6200 675.6500 1040.0000 675.9500 ;
      RECT 0.0000 669.9500 1040.0000 675.6500 ;
      RECT 0.6200 669.6500 1040.0000 669.9500 ;
      RECT 0.0000 663.9500 1040.0000 669.6500 ;
      RECT 0.6200 663.6500 1040.0000 663.9500 ;
      RECT 0.0000 657.9500 1040.0000 663.6500 ;
      RECT 0.6200 657.6500 1040.0000 657.9500 ;
      RECT 0.0000 651.9500 1040.0000 657.6500 ;
      RECT 0.6200 651.6500 1040.0000 651.9500 ;
      RECT 0.0000 645.9500 1040.0000 651.6500 ;
      RECT 0.6200 645.6500 1040.0000 645.9500 ;
      RECT 0.0000 639.9500 1040.0000 645.6500 ;
      RECT 0.6200 639.6500 1040.0000 639.9500 ;
      RECT 0.0000 633.9500 1040.0000 639.6500 ;
      RECT 0.6200 633.6500 1040.0000 633.9500 ;
      RECT 0.0000 627.9500 1040.0000 633.6500 ;
      RECT 0.6200 627.6500 1040.0000 627.9500 ;
      RECT 0.0000 621.9500 1040.0000 627.6500 ;
      RECT 0.6200 621.6500 1040.0000 621.9500 ;
      RECT 0.0000 615.9500 1040.0000 621.6500 ;
      RECT 0.6200 615.6500 1040.0000 615.9500 ;
      RECT 0.0000 609.9500 1040.0000 615.6500 ;
      RECT 0.6200 609.6500 1040.0000 609.9500 ;
      RECT 0.0000 603.9500 1040.0000 609.6500 ;
      RECT 0.6200 603.6500 1040.0000 603.9500 ;
      RECT 0.0000 597.9500 1040.0000 603.6500 ;
      RECT 0.6200 597.6500 1040.0000 597.9500 ;
      RECT 0.0000 591.9500 1040.0000 597.6500 ;
      RECT 0.6200 591.6500 1040.0000 591.9500 ;
      RECT 0.0000 585.9500 1040.0000 591.6500 ;
      RECT 0.6200 585.6500 1040.0000 585.9500 ;
      RECT 0.0000 579.9500 1040.0000 585.6500 ;
      RECT 0.6200 579.6500 1040.0000 579.9500 ;
      RECT 0.0000 573.9500 1040.0000 579.6500 ;
      RECT 0.6200 573.6500 1040.0000 573.9500 ;
      RECT 0.0000 567.9500 1040.0000 573.6500 ;
      RECT 0.6200 567.6500 1040.0000 567.9500 ;
      RECT 0.0000 561.9500 1040.0000 567.6500 ;
      RECT 0.6200 561.6500 1040.0000 561.9500 ;
      RECT 0.0000 555.9500 1040.0000 561.6500 ;
      RECT 0.6200 555.6500 1040.0000 555.9500 ;
      RECT 0.0000 549.9500 1040.0000 555.6500 ;
      RECT 0.6200 549.6500 1040.0000 549.9500 ;
      RECT 0.0000 543.9500 1040.0000 549.6500 ;
      RECT 0.6200 543.6500 1040.0000 543.9500 ;
      RECT 0.0000 537.9500 1040.0000 543.6500 ;
      RECT 0.6200 537.6500 1040.0000 537.9500 ;
      RECT 0.0000 531.9500 1040.0000 537.6500 ;
      RECT 0.6200 531.6500 1040.0000 531.9500 ;
      RECT 0.0000 525.9500 1040.0000 531.6500 ;
      RECT 0.6200 525.6500 1040.0000 525.9500 ;
      RECT 0.0000 519.9500 1040.0000 525.6500 ;
      RECT 0.6200 519.6500 1040.0000 519.9500 ;
      RECT 0.0000 513.9500 1040.0000 519.6500 ;
      RECT 0.6200 513.6500 1040.0000 513.9500 ;
      RECT 0.0000 507.9500 1040.0000 513.6500 ;
      RECT 0.6200 507.6500 1040.0000 507.9500 ;
      RECT 0.0000 501.9500 1040.0000 507.6500 ;
      RECT 0.6200 501.6500 1040.0000 501.9500 ;
      RECT 0.0000 495.9500 1040.0000 501.6500 ;
      RECT 0.6200 495.6500 1040.0000 495.9500 ;
      RECT 0.0000 489.9500 1040.0000 495.6500 ;
      RECT 0.6200 489.6500 1040.0000 489.9500 ;
      RECT 0.0000 483.9500 1040.0000 489.6500 ;
      RECT 0.6200 483.6500 1040.0000 483.9500 ;
      RECT 0.0000 477.9500 1040.0000 483.6500 ;
      RECT 0.6200 477.6500 1040.0000 477.9500 ;
      RECT 0.0000 471.9500 1040.0000 477.6500 ;
      RECT 0.6200 471.6500 1040.0000 471.9500 ;
      RECT 0.0000 465.9500 1040.0000 471.6500 ;
      RECT 0.6200 465.6500 1040.0000 465.9500 ;
      RECT 0.0000 459.9500 1040.0000 465.6500 ;
      RECT 0.6200 459.6500 1040.0000 459.9500 ;
      RECT 0.0000 453.9500 1040.0000 459.6500 ;
      RECT 0.6200 453.6500 1040.0000 453.9500 ;
      RECT 0.0000 447.9500 1040.0000 453.6500 ;
      RECT 0.6200 447.6500 1040.0000 447.9500 ;
      RECT 0.0000 441.9500 1040.0000 447.6500 ;
      RECT 0.6200 441.6500 1040.0000 441.9500 ;
      RECT 0.0000 435.9500 1040.0000 441.6500 ;
      RECT 0.6200 435.6500 1040.0000 435.9500 ;
      RECT 0.0000 429.9500 1040.0000 435.6500 ;
      RECT 0.6200 429.6500 1040.0000 429.9500 ;
      RECT 0.0000 423.9500 1040.0000 429.6500 ;
      RECT 0.6200 423.6500 1040.0000 423.9500 ;
      RECT 0.0000 417.9500 1040.0000 423.6500 ;
      RECT 0.6200 417.6500 1040.0000 417.9500 ;
      RECT 0.0000 411.9500 1040.0000 417.6500 ;
      RECT 0.6200 411.6500 1040.0000 411.9500 ;
      RECT 0.0000 405.9500 1040.0000 411.6500 ;
      RECT 0.6200 405.6500 1040.0000 405.9500 ;
      RECT 0.0000 399.9500 1040.0000 405.6500 ;
      RECT 0.6200 399.6500 1040.0000 399.9500 ;
      RECT 0.0000 393.9500 1040.0000 399.6500 ;
      RECT 0.6200 393.6500 1040.0000 393.9500 ;
      RECT 0.0000 387.9500 1040.0000 393.6500 ;
      RECT 0.6200 387.6500 1040.0000 387.9500 ;
      RECT 0.0000 381.9500 1040.0000 387.6500 ;
      RECT 0.6200 381.6500 1040.0000 381.9500 ;
      RECT 0.0000 375.9500 1040.0000 381.6500 ;
      RECT 0.6200 375.6500 1040.0000 375.9500 ;
      RECT 0.0000 369.9500 1040.0000 375.6500 ;
      RECT 0.6200 369.6500 1040.0000 369.9500 ;
      RECT 0.0000 363.9500 1040.0000 369.6500 ;
      RECT 0.6200 363.6500 1040.0000 363.9500 ;
      RECT 0.0000 357.9500 1040.0000 363.6500 ;
      RECT 0.6200 357.6500 1040.0000 357.9500 ;
      RECT 0.0000 351.9500 1040.0000 357.6500 ;
      RECT 0.6200 351.6500 1040.0000 351.9500 ;
      RECT 0.0000 345.9500 1040.0000 351.6500 ;
      RECT 0.6200 345.6500 1040.0000 345.9500 ;
      RECT 0.0000 339.9500 1040.0000 345.6500 ;
      RECT 0.6200 339.6500 1040.0000 339.9500 ;
      RECT 0.0000 333.9500 1040.0000 339.6500 ;
      RECT 0.6200 333.6500 1040.0000 333.9500 ;
      RECT 0.0000 327.9500 1040.0000 333.6500 ;
      RECT 0.6200 327.6500 1040.0000 327.9500 ;
      RECT 0.0000 321.9500 1040.0000 327.6500 ;
      RECT 0.6200 321.6500 1040.0000 321.9500 ;
      RECT 0.0000 315.9500 1040.0000 321.6500 ;
      RECT 0.6200 315.6500 1040.0000 315.9500 ;
      RECT 0.0000 309.9500 1040.0000 315.6500 ;
      RECT 0.6200 309.6500 1040.0000 309.9500 ;
      RECT 0.0000 303.9500 1040.0000 309.6500 ;
      RECT 0.6200 303.6500 1040.0000 303.9500 ;
      RECT 0.0000 297.9500 1040.0000 303.6500 ;
      RECT 0.6200 297.6500 1040.0000 297.9500 ;
      RECT 0.0000 291.9500 1040.0000 297.6500 ;
      RECT 0.6200 291.6500 1040.0000 291.9500 ;
      RECT 0.0000 285.9500 1040.0000 291.6500 ;
      RECT 0.6200 285.6500 1040.0000 285.9500 ;
      RECT 0.0000 279.9500 1040.0000 285.6500 ;
      RECT 0.6200 279.6500 1040.0000 279.9500 ;
      RECT 0.0000 273.9500 1040.0000 279.6500 ;
      RECT 0.6200 273.6500 1040.0000 273.9500 ;
      RECT 0.0000 267.9500 1040.0000 273.6500 ;
      RECT 0.6200 267.6500 1040.0000 267.9500 ;
      RECT 0.0000 0.0000 1040.0000 267.6500 ;
    LAYER M4 ;
      RECT 0.0000 0.6200 1040.0000 1040.0000 ;
      RECT 973.2500 0.0000 1040.0000 0.6200 ;
      RECT 967.2500 0.0000 972.9500 0.6200 ;
      RECT 961.2500 0.0000 966.9500 0.6200 ;
      RECT 955.2500 0.0000 960.9500 0.6200 ;
      RECT 949.2500 0.0000 954.9500 0.6200 ;
      RECT 943.2500 0.0000 948.9500 0.6200 ;
      RECT 937.2500 0.0000 942.9500 0.6200 ;
      RECT 931.2500 0.0000 936.9500 0.6200 ;
      RECT 925.2500 0.0000 930.9500 0.6200 ;
      RECT 919.2500 0.0000 924.9500 0.6200 ;
      RECT 913.2500 0.0000 918.9500 0.6200 ;
      RECT 907.2500 0.0000 912.9500 0.6200 ;
      RECT 901.2500 0.0000 906.9500 0.6200 ;
      RECT 895.2500 0.0000 900.9500 0.6200 ;
      RECT 889.2500 0.0000 894.9500 0.6200 ;
      RECT 883.2500 0.0000 888.9500 0.6200 ;
      RECT 877.2500 0.0000 882.9500 0.6200 ;
      RECT 871.2500 0.0000 876.9500 0.6200 ;
      RECT 865.2500 0.0000 870.9500 0.6200 ;
      RECT 859.2500 0.0000 864.9500 0.6200 ;
      RECT 853.2500 0.0000 858.9500 0.6200 ;
      RECT 847.2500 0.0000 852.9500 0.6200 ;
      RECT 841.2500 0.0000 846.9500 0.6200 ;
      RECT 835.2500 0.0000 840.9500 0.6200 ;
      RECT 829.2500 0.0000 834.9500 0.6200 ;
      RECT 823.2500 0.0000 828.9500 0.6200 ;
      RECT 817.2500 0.0000 822.9500 0.6200 ;
      RECT 811.2500 0.0000 816.9500 0.6200 ;
      RECT 805.2500 0.0000 810.9500 0.6200 ;
      RECT 799.2500 0.0000 804.9500 0.6200 ;
      RECT 793.2500 0.0000 798.9500 0.6200 ;
      RECT 787.2500 0.0000 792.9500 0.6200 ;
      RECT 781.2500 0.0000 786.9500 0.6200 ;
      RECT 775.2500 0.0000 780.9500 0.6200 ;
      RECT 769.2500 0.0000 774.9500 0.6200 ;
      RECT 763.2500 0.0000 768.9500 0.6200 ;
      RECT 757.2500 0.0000 762.9500 0.6200 ;
      RECT 751.2500 0.0000 756.9500 0.6200 ;
      RECT 745.2500 0.0000 750.9500 0.6200 ;
      RECT 739.2500 0.0000 744.9500 0.6200 ;
      RECT 733.2500 0.0000 738.9500 0.6200 ;
      RECT 727.2500 0.0000 732.9500 0.6200 ;
      RECT 721.2500 0.0000 726.9500 0.6200 ;
      RECT 715.2500 0.0000 720.9500 0.6200 ;
      RECT 709.2500 0.0000 714.9500 0.6200 ;
      RECT 703.2500 0.0000 708.9500 0.6200 ;
      RECT 697.2500 0.0000 702.9500 0.6200 ;
      RECT 691.2500 0.0000 696.9500 0.6200 ;
      RECT 685.2500 0.0000 690.9500 0.6200 ;
      RECT 679.2500 0.0000 684.9500 0.6200 ;
      RECT 673.2500 0.0000 678.9500 0.6200 ;
      RECT 667.2500 0.0000 672.9500 0.6200 ;
      RECT 661.2500 0.0000 666.9500 0.6200 ;
      RECT 655.2500 0.0000 660.9500 0.6200 ;
      RECT 649.2500 0.0000 654.9500 0.6200 ;
      RECT 643.2500 0.0000 648.9500 0.6200 ;
      RECT 637.2500 0.0000 642.9500 0.6200 ;
      RECT 631.2500 0.0000 636.9500 0.6200 ;
      RECT 625.2500 0.0000 630.9500 0.6200 ;
      RECT 619.2500 0.0000 624.9500 0.6200 ;
      RECT 613.2500 0.0000 618.9500 0.6200 ;
      RECT 607.2500 0.0000 612.9500 0.6200 ;
      RECT 601.2500 0.0000 606.9500 0.6200 ;
      RECT 595.2500 0.0000 600.9500 0.6200 ;
      RECT 589.2500 0.0000 594.9500 0.6200 ;
      RECT 583.2500 0.0000 588.9500 0.6200 ;
      RECT 577.2500 0.0000 582.9500 0.6200 ;
      RECT 571.2500 0.0000 576.9500 0.6200 ;
      RECT 565.2500 0.0000 570.9500 0.6200 ;
      RECT 559.2500 0.0000 564.9500 0.6200 ;
      RECT 553.2500 0.0000 558.9500 0.6200 ;
      RECT 547.2500 0.0000 552.9500 0.6200 ;
      RECT 541.2500 0.0000 546.9500 0.6200 ;
      RECT 535.2500 0.0000 540.9500 0.6200 ;
      RECT 529.2500 0.0000 534.9500 0.6200 ;
      RECT 523.2500 0.0000 528.9500 0.6200 ;
      RECT 517.2500 0.0000 522.9500 0.6200 ;
      RECT 511.2500 0.0000 516.9500 0.6200 ;
      RECT 505.2500 0.0000 510.9500 0.6200 ;
      RECT 499.2500 0.0000 504.9500 0.6200 ;
      RECT 493.2500 0.0000 498.9500 0.6200 ;
      RECT 487.2500 0.0000 492.9500 0.6200 ;
      RECT 481.2500 0.0000 486.9500 0.6200 ;
      RECT 475.2500 0.0000 480.9500 0.6200 ;
      RECT 469.2500 0.0000 474.9500 0.6200 ;
      RECT 463.2500 0.0000 468.9500 0.6200 ;
      RECT 457.2500 0.0000 462.9500 0.6200 ;
      RECT 451.2500 0.0000 456.9500 0.6200 ;
      RECT 445.2500 0.0000 450.9500 0.6200 ;
      RECT 439.2500 0.0000 444.9500 0.6200 ;
      RECT 433.2500 0.0000 438.9500 0.6200 ;
      RECT 427.2500 0.0000 432.9500 0.6200 ;
      RECT 421.2500 0.0000 426.9500 0.6200 ;
      RECT 415.2500 0.0000 420.9500 0.6200 ;
      RECT 409.2500 0.0000 414.9500 0.6200 ;
      RECT 403.2500 0.0000 408.9500 0.6200 ;
      RECT 397.2500 0.0000 402.9500 0.6200 ;
      RECT 391.2500 0.0000 396.9500 0.6200 ;
      RECT 385.2500 0.0000 390.9500 0.6200 ;
      RECT 379.2500 0.0000 384.9500 0.6200 ;
      RECT 373.2500 0.0000 378.9500 0.6200 ;
      RECT 367.2500 0.0000 372.9500 0.6200 ;
      RECT 361.2500 0.0000 366.9500 0.6200 ;
      RECT 355.2500 0.0000 360.9500 0.6200 ;
      RECT 349.2500 0.0000 354.9500 0.6200 ;
      RECT 343.2500 0.0000 348.9500 0.6200 ;
      RECT 337.2500 0.0000 342.9500 0.6200 ;
      RECT 331.2500 0.0000 336.9500 0.6200 ;
      RECT 325.2500 0.0000 330.9500 0.6200 ;
      RECT 319.2500 0.0000 324.9500 0.6200 ;
      RECT 313.2500 0.0000 318.9500 0.6200 ;
      RECT 307.2500 0.0000 312.9500 0.6200 ;
      RECT 301.2500 0.0000 306.9500 0.6200 ;
      RECT 295.2500 0.0000 300.9500 0.6200 ;
      RECT 289.2500 0.0000 294.9500 0.6200 ;
      RECT 283.2500 0.0000 288.9500 0.6200 ;
      RECT 277.2500 0.0000 282.9500 0.6200 ;
      RECT 271.2500 0.0000 276.9500 0.6200 ;
      RECT 265.2500 0.0000 270.9500 0.6200 ;
      RECT 259.2500 0.0000 264.9500 0.6200 ;
      RECT 253.2500 0.0000 258.9500 0.6200 ;
      RECT 247.2500 0.0000 252.9500 0.6200 ;
      RECT 241.2500 0.0000 246.9500 0.6200 ;
      RECT 235.2500 0.0000 240.9500 0.6200 ;
      RECT 229.2500 0.0000 234.9500 0.6200 ;
      RECT 223.2500 0.0000 228.9500 0.6200 ;
      RECT 217.2500 0.0000 222.9500 0.6200 ;
      RECT 211.2500 0.0000 216.9500 0.6200 ;
      RECT 205.2500 0.0000 210.9500 0.6200 ;
      RECT 199.2500 0.0000 204.9500 0.6200 ;
      RECT 193.2500 0.0000 198.9500 0.6200 ;
      RECT 187.2500 0.0000 192.9500 0.6200 ;
      RECT 181.2500 0.0000 186.9500 0.6200 ;
      RECT 175.2500 0.0000 180.9500 0.6200 ;
      RECT 169.2500 0.0000 174.9500 0.6200 ;
      RECT 163.2500 0.0000 168.9500 0.6200 ;
      RECT 157.2500 0.0000 162.9500 0.6200 ;
      RECT 151.2500 0.0000 156.9500 0.6200 ;
      RECT 145.2500 0.0000 150.9500 0.6200 ;
      RECT 139.2500 0.0000 144.9500 0.6200 ;
      RECT 133.2500 0.0000 138.9500 0.6200 ;
      RECT 127.2500 0.0000 132.9500 0.6200 ;
      RECT 121.2500 0.0000 126.9500 0.6200 ;
      RECT 115.2500 0.0000 120.9500 0.6200 ;
      RECT 109.2500 0.0000 114.9500 0.6200 ;
      RECT 103.2500 0.0000 108.9500 0.6200 ;
      RECT 97.2500 0.0000 102.9500 0.6200 ;
      RECT 91.2500 0.0000 96.9500 0.6200 ;
      RECT 85.2500 0.0000 90.9500 0.6200 ;
      RECT 79.2500 0.0000 84.9500 0.6200 ;
      RECT 73.2500 0.0000 78.9500 0.6200 ;
      RECT 67.2500 0.0000 72.9500 0.6200 ;
      RECT 0.0000 0.0000 66.9500 0.6200 ;
    LAYER M5 ;
      RECT 0.0000 0.0000 1040.0000 1040.0000 ;
    LAYER M6 ;
      RECT 0.0000 0.0000 1040.0000 1040.0000 ;
    LAYER M7 ;
      RECT 0.0000 0.0000 1040.0000 1040.0000 ;
    LAYER M8 ;
      RECT 0.0000 0.0000 1040.0000 1040.0000 ;
  END
END core

END LIBRARY
